One B-rep face of a CAD part: STEP entity #123.
In plain terms, the planar face has unit normal (0, 0, 1).
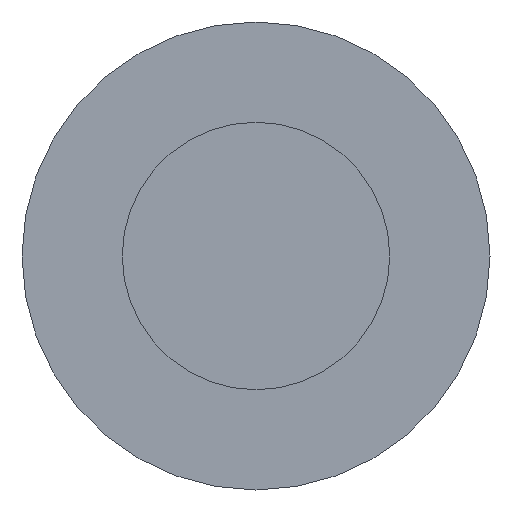
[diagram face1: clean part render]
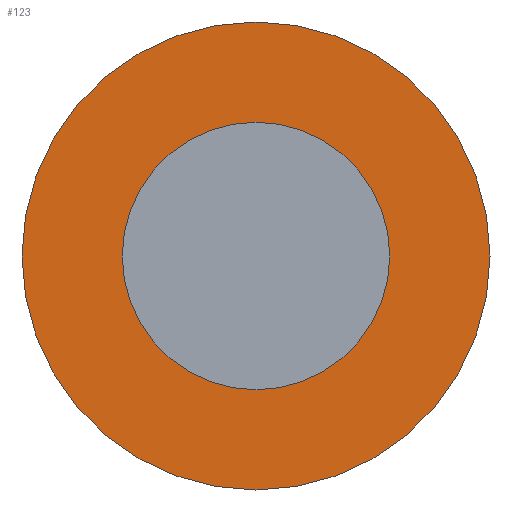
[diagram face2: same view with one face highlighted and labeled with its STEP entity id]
Its self-contained STEP definition (entity closure, numbers rounded to 3 decimals):
#39 = EDGE_CURVE('',#40,#40,#42,.T.);
#40 = VERTEX_POINT('',#41);
#41 = CARTESIAN_POINT('',(1.75,0.,0.));
#42 = SURFACE_CURVE('',#43,(#48,#60),.PCURVE_S1.);
#43 = CIRCLE('',#44,1.75);
#44 = AXIS2_PLACEMENT_3D('',#45,#46,#47);
#45 = CARTESIAN_POINT('',(0.,0.,0.));
#46 = DIRECTION('',(0.,0.,1.));
#47 = DIRECTION('',(1.,0.,-0.));
#48 = PCURVE('',#49,#54);
#49 = CYLINDRICAL_SURFACE('',#50,1.75);
#50 = AXIS2_PLACEMENT_3D('',#51,#52,#53);
#51 = CARTESIAN_POINT('',(0.,0.,-1.3));
#52 = DIRECTION('',(0.,0.,1.));
#53 = DIRECTION('',(1.,0.,-0.));
#54 = DEFINITIONAL_REPRESENTATION('',(#55),#59);
#55 = LINE('',#56,#57);
#56 = CARTESIAN_POINT('',(0.,1.3));
#57 = VECTOR('',#58,1.);
#58 = DIRECTION('',(1.,0.));
#59 = ( GEOMETRIC_REPRESENTATION_CONTEXT(2) 
PARAMETRIC_REPRESENTATION_CONTEXT() REPRESENTATION_CONTEXT('2D SPACE',''
  ) );
#60 = PCURVE('',#61,#66);
#61 = PLANE('',#62);
#62 = AXIS2_PLACEMENT_3D('',#63,#64,#65);
#63 = CARTESIAN_POINT('',(0.,0.,0.));
#64 = DIRECTION('',(0.,0.,1.));
#65 = DIRECTION('',(1.,0.,-0.));
#66 = DEFINITIONAL_REPRESENTATION('',(#67),#71);
#67 = CIRCLE('',#68,1.75);
#68 = AXIS2_PLACEMENT_2D('',#69,#70);
#69 = CARTESIAN_POINT('',(0.,0.));
#70 = DIRECTION('',(1.,0.));
#71 = ( GEOMETRIC_REPRESENTATION_CONTEXT(2) 
PARAMETRIC_REPRESENTATION_CONTEXT() REPRESENTATION_CONTEXT('2D SPACE',''
  ) );
#123 = ADVANCED_FACE('',(#124,#127),#61,.T.);
#124 = FACE_BOUND('',#125,.T.);
#125 = EDGE_LOOP('',(#126));
#126 = ORIENTED_EDGE('',*,*,#39,.T.);
#127 = FACE_BOUND('',#128,.T.);
#128 = EDGE_LOOP('',(#129));
#129 = ORIENTED_EDGE('',*,*,#130,.F.);
#130 = EDGE_CURVE('',#131,#131,#133,.T.);
#131 = VERTEX_POINT('',#132);
#132 = CARTESIAN_POINT('',(1.,0.,0.));
#133 = SURFACE_CURVE('',#134,(#139,#146),.PCURVE_S1.);
#134 = CIRCLE('',#135,1.);
#135 = AXIS2_PLACEMENT_3D('',#136,#137,#138);
#136 = CARTESIAN_POINT('',(0.,0.,0.));
#137 = DIRECTION('',(0.,0.,1.));
#138 = DIRECTION('',(1.,0.,-0.));
#139 = PCURVE('',#61,#140);
#140 = DEFINITIONAL_REPRESENTATION('',(#141),#145);
#141 = CIRCLE('',#142,1.);
#142 = AXIS2_PLACEMENT_2D('',#143,#144);
#143 = CARTESIAN_POINT('',(0.,0.));
#144 = DIRECTION('',(1.,0.));
#145 = ( GEOMETRIC_REPRESENTATION_CONTEXT(2) 
PARAMETRIC_REPRESENTATION_CONTEXT() REPRESENTATION_CONTEXT('2D SPACE',''
  ) );
#146 = PCURVE('',#147,#152);
#147 = CYLINDRICAL_SURFACE('',#148,1.);
#148 = AXIS2_PLACEMENT_3D('',#149,#150,#151);
#149 = CARTESIAN_POINT('',(0.,0.,0.));
#150 = DIRECTION('',(0.,0.,1.));
#151 = DIRECTION('',(1.,0.,-0.));
#152 = DEFINITIONAL_REPRESENTATION('',(#153),#157);
#153 = LINE('',#154,#155);
#154 = CARTESIAN_POINT('',(0.,0.));
#155 = VECTOR('',#156,1.);
#156 = DIRECTION('',(1.,0.));
#157 = ( GEOMETRIC_REPRESENTATION_CONTEXT(2) 
PARAMETRIC_REPRESENTATION_CONTEXT() REPRESENTATION_CONTEXT('2D SPACE',''
  ) );
